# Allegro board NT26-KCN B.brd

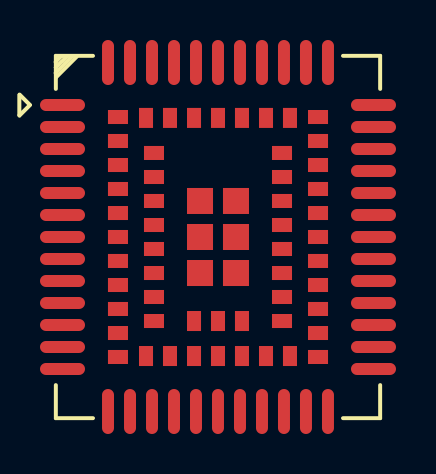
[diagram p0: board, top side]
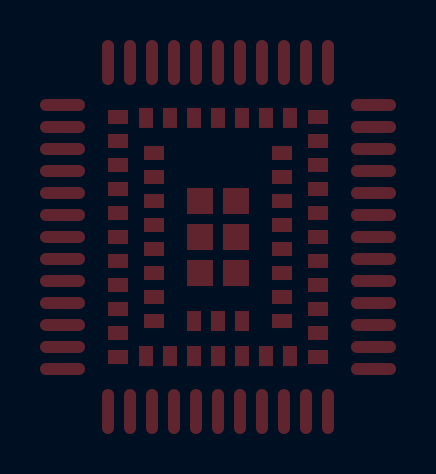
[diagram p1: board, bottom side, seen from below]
No outline. copper layers: TOP, BOTTOM. Coordinates in mm from the lowest, leftmost part position.

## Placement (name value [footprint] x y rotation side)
UNK#REF  -  [unnamed]  0 0 0 top

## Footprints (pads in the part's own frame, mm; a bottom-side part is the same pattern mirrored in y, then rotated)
unnamed
  oval 2.25x0.599 smd: 1(-7.775,6.599) 2(-7.775,5.499) 3(-7.775,4.399) 4(-7.775,3.299) 5(-7.775,2.2) 6(-7.775,1.1) 7(-7.775,0) 8(-7.775,-1.1) 9(-7.775,-2.2) 10(-7.775,-3.299) 11(-7.775,-4.399) 12(-7.775,-5.499) 13(-7.775,-6.599) 23(7.775,-6.599) 24(7.775,-5.499) 25(7.775,-4.399) 26(7.775,-3.299) 27(7.775,-2.2) 28(7.775,-1.1) 29(7.775,0) 30(7.775,1.1) 31(7.775,2.2) 32(7.775,3.299) 33(7.775,4.399) 34(7.775,5.499) 35(7.775,6.599)
  oval 0.599x2.25 smd: 14(-4.399,-8.725) 15(-3.299,-8.725) 16(-2.2,-8.725) 17(-1.1,-8.725) 18(0,-8.725) 19(1.1,-8.725) 20(2.2,-8.725) 21(3.299,-8.725) 22(4.399,-8.725) 36(4.399,8.725) 37(3.299,8.725) 38(2.2,8.725) 39(1.1,8.725) 40(0,8.725) 41(-1.1,8.725) 42(-2.2,8.725) 43(-3.299,8.725) 44(-4.399,8.725) 95(-5.499,-8.725) 96(5.499,-8.725) 97(5.499,8.725) 98(-5.499,8.725)
  rect 1.001x0.701 smd: 45(-5.001,4.801) 46(-5.001,3.599) 47(-5.001,2.4) 48(-5.001,1.199) 49(-5.001,0) 50(-5.001,-1.199) 51(-5.001,-2.4) 52(-5.001,-3.599) 53(-5.001,-4.801) 59(5.001,-4.801) 60(5.001,-3.599) 61(5.001,-2.4) 62(5.001,-1.199) 63(5.001,0) 64(5.001,1.199) 65(5.001,2.4) 66(5.001,3.599) 67(5.001,4.801) 73(-3.2,4.201) 74(-3.2,3) 75(-3.2,1.801) 76(-3.2,0.599) 77(-3.2,-0.599) 78(-3.2,-1.801) 79(-3.2,-3) 80(-3.2,-4.201) 81(3.2,-4.201) 82(3.2,-3) 83(3.2,-1.801) 84(3.2,-0.599) 85(3.2,0.599) 86(3.2,1.801) 87(3.2,3) 88(3.2,4.201) 99(-5.001,5.999) 100(-5.001,-5.999) 103(5.001,-5.999) 104(5.001,5.999)
  rect 0.701x1.001 smd: 54(-2.4,-5.951) 55(-1.199,-5.951) 56(0,-5.951) 57(1.199,-5.951) 58(2.4,-5.951) 68(2.4,5.954) 69(1.199,5.954) 70(0,5.954) 71(-1.199,5.954) 72(-2.4,5.954) 101(-3.599,-5.951) 102(3.599,-5.951) 105(3.599,5.954) 106(-3.599,5.954) 107(-1.199,-4.201) 108(0,-4.201) 109(1.199,-4.201)
  rect 1.3x1.3 smd: 89(-0.899,1.801) 90(-0.899,0) 91(-0.899,-1.801) 92(0.899,-1.801) 93(0.899,0) 94(0.899,1.801)

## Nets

Pads without a net: UNK#REF 1 2 3 4 5 6 7 8 9 10 11 12 13 14 15 16 17 18 19 20 21 22 23 24 25 26 27 28 29 30 31 32 33 34 35 36 37 38 39 40 41 42 43 44 45 46 47 48 49 50 51 52 53 54 55 56 57 58 59 60 61 62 63 64 65 66 67 68 69 70 71 72 73 74 75 76 77 78 79 80 81 82 83 84 85 86 87 88 89 90 91 92 93 94 95 96 97 98 99 100 101 102 103 104 105 106 107 108 109
